VERSION 5.7 ;
NOWIREEXTENSIONATPIN ON ;
DIVIDERCHAR "/" ;
BUSBITCHARS "[]" ;
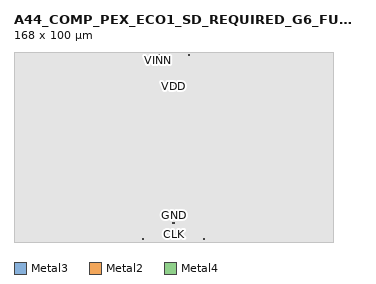
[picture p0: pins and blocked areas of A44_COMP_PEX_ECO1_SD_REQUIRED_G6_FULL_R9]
MACRO A44_COMP_PEX_ECO1_SD_REQUIRED_G6_FULL_R9
  CLASS BLOCK ;
  FOREIGN A44_COMP_PEX_ECO1_SD_REQUIRED_G6_FULL_R9 ;
  ORIGIN 0.000 0.000 ;
  SIZE 168.000 BY 100.000 ;
  SYMMETRY X Y ;
  PIN CLK
    DIRECTION INPUT ;
    USE SIGNAL ;
    PORT
      LAYER Metal3 ;
        RECT 83.600 1.100 84.400 1.900 ;
    END
  END CLK
  PIN DCMPP
    DIRECTION OUTPUT ;
    USE SIGNAL ;
    PORT
      LAYER Metal2 ;
        RECT 67.600 1.100 68.400 1.900 ;
    END
  END DCMPP
  PIN VINP
    DIRECTION INPUT ;
    USE SIGNAL ;
    PORT
      LAYER Metal3 ;
        RECT 91.600 98.100 92.400 98.900 ;
    END
  END VINP
  PIN DCMPN
    DIRECTION OUTPUT ;
    USE SIGNAL ;
    PORT
      LAYER Metal2 ;
        RECT 99.600 1.100 100.400 1.900 ;
    END
  END DCMPN
  PIN VINN
    DIRECTION INPUT ;
    USE SIGNAL ;
    PORT
      LAYER Metal3 ;
        RECT 75.600 98.100 76.400 98.900 ;
    END
  END VINN
  PIN VDD
    DIRECTION INOUT ;
    USE POWER ;
    PORT
      LAYER Metal4 ;
        RECT 83.500 81.500 84.500 82.500 ;
    END
  END VDD
  PIN GND
    DIRECTION INOUT ;
    USE GROUND ;
    PORT
      LAYER Metal4 ;
        RECT 83.500 9.500 84.500 10.500 ;
    END
  END GND
  OBS
    LAYER Metal1 ;
      RECT 0.000 0.000 168.000 100.000 ;
    LAYER Metal2 ;
      RECT 0.000 0.000 168.000 100.000 ;
    LAYER Metal3 ;
      RECT 0.000 0.000 168.000 100.000 ;
    LAYER Metal4 ;
      RECT 0.000 0.000 168.000 100.000 ;
    LAYER Metal5 ;
      RECT 0.000 0.000 168.000 100.000 ;
  END
END A44_COMP_PEX_ECO1_SD_REQUIRED_G6_FULL_R9
END LIBRARY
